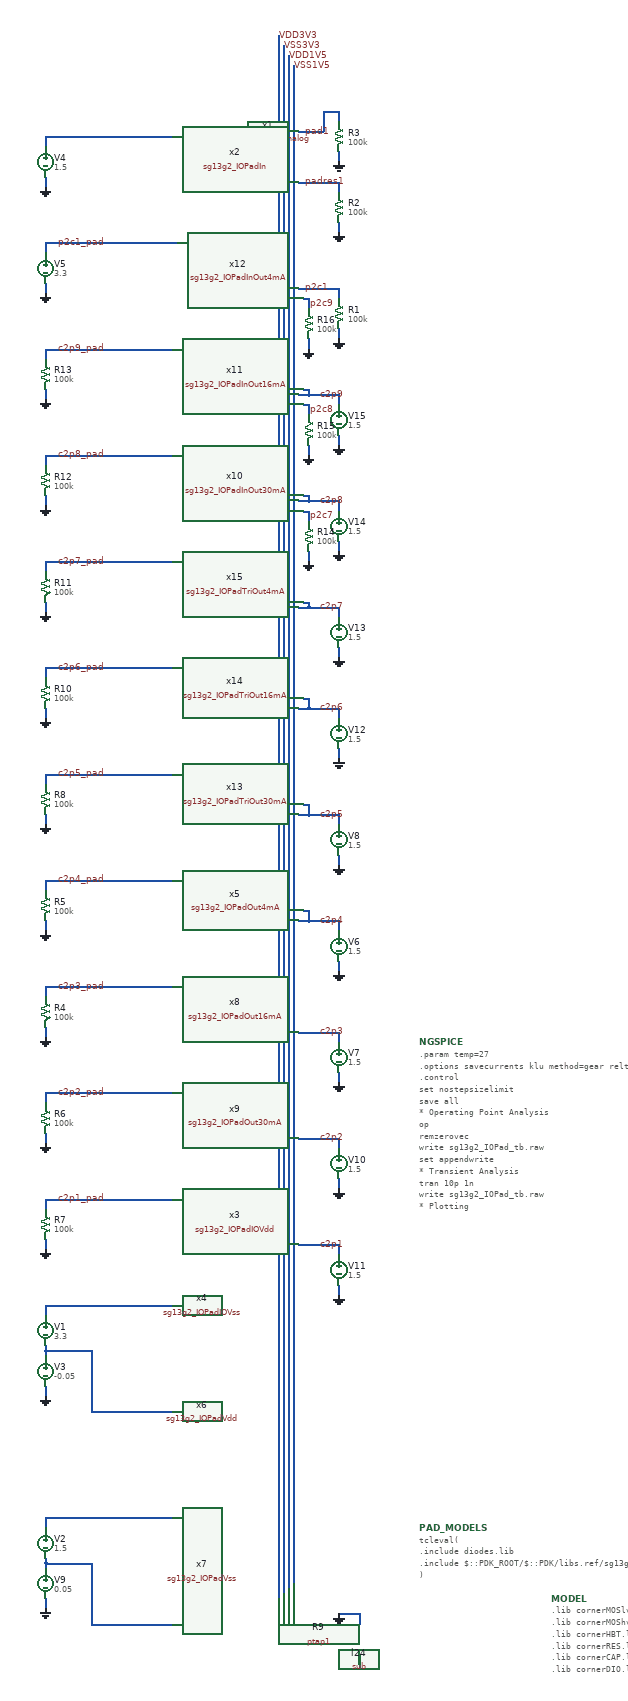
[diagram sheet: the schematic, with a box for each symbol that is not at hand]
v {xschem version=3.4.8RC file_version=1.3}
G {}
K {}
V {}
S {}
F {}
E {}
N 100 -450 100 -430 {lab=VDD1V5}
N 100 -870 100 -850 {lab=VDD3V3}
N 100 -710 100 -690 {lab=GND}
N 100 -3100 100 -3080 {lab=GND}
N 100 -3180 100 -3160 {lab=pad1}
N 100 -2890 100 -2870 {lab=GND}
N 100 -2970 100 -2950 {lab=p2c1_pad}
N 680 -1330 680 -1310 {lab=GND}
N 680 -1410 680 -1390 {lab=c2p3}
N 600 -1410 680 -1410 {lab=c2p3}
N 100 -290 100 -270 {lab=GND}
N 100 -360 100 -350 {lab=VSS1V5}
N 100 -780 100 -770 {lab=VSS3V3}
N 190 -360 190 -240 {lab=VSS1V5}
N 100 -360 190 -360 {lab=VSS1V5}
N 100 -370 100 -360 {lab=VSS1V5}
N 680 -1120 680 -1100 {lab=GND}
N 680 -1200 680 -1180 {lab=c2p2}
N 600 -1200 680 -1200 {lab=c2p2}
N 680 -910 680 -890 {lab=GND}
N 680 -990 680 -970 {lab=c2p1}
N 600 -990 680 -990 {lab=c2p1}
N 720 -180 720 -160 {lab=sub!}
N 720 -260 720 -240 {lab=GND}
N 680 -260 720 -260 {lab=GND}
N 190 -240 350 -240 {lab=VSS1V5}
N 100 -450 350 -450 {lab=VDD1V5}
N 100 -870 350 -870 {lab=VDD3V3}
N 100 -780 190 -780 {lab=VSS3V3}
N 100 -790 100 -780 {lab=VSS3V3}
N 190 -780 190 -660 {lab=VSS3V3}
N 190 -660 350 -660 {lab=VSS3V3}
N 100 -1000 100 -980 {lab=GND}
N 100 -1080 100 -1060 {lab=c2p1_pad}
N 100 -1080 350 -1080 {lab=c2p1_pad}
N 100 -1290 100 -1270 {lab=c2p2_pad}
N 100 -1290 350 -1290 {lab=c2p2_pad}
N 100 -1210 100 -1190 {lab=GND}
N 100 -1500 100 -1480 {lab=c2p3_pad}
N 100 -1500 350 -1500 {lab=c2p3_pad}
N 100 -1420 100 -1400 {lab=GND}
N 680 -2880 680 -2860 {lab=p2c1}
N 600 -2880 680 -2880 {lab=p2c1}
N 680 -2800 680 -2780 {lab=GND}
N 680 -3090 680 -3070 {lab=padres1}
N 680 -3010 680 -2990 {lab=GND}
N 600 -3090 680 -3090 {lab=padres1}
N 680 -3230 680 -3210 {lab=pad1}
N 680 -3150 680 -3130 {lab=GND}
N 600 -3190 650 -3190 {lab=pad1}
N 650 -3230 650 -3190 {lab=pad1}
N 650 -3230 680 -3230 {lab=pad1}
N 100 -2970 360 -2970 {lab=p2c1_pad}
N 100 -3180 350 -3180 {lab=pad1}
N 590 -3320 590 -320 {lab=VSS1V5}
N 580 -3340 580 -310 {lab=VDD1V5}
N 570 -3360 570 -300 {lab=VSS3V3}
N 560 -3380 560 -290 {lab=VDD3V3}
N 680 -1550 680 -1530 {lab=GND}
N 680 -1630 680 -1610 {lab=c2p4}
N 620 -1630 680 -1630 {lab=c2p4}
N 680 -1760 680 -1740 {lab=GND}
N 680 -1840 680 -1820 {lab=c2p5}
N 620 -1840 680 -1840 {lab=c2p5}
N 680 -1970 680 -1950 {lab=GND}
N 680 -2050 680 -2030 {lab=c2p6}
N 620 -2050 680 -2050 {lab=c2p6}
N 680 -2170 680 -2150 {lab=GND}
N 680 -2250 680 -2230 {lab=c2p7}
N 620 -2250 680 -2250 {lab=c2p7}
N 680 -2380 680 -2360 {lab=GND}
N 680 -2460 680 -2440 {lab=c2p8}
N 620 -2460 680 -2460 {lab=c2p8}
N 680 -2590 680 -2570 {lab=GND}
N 680 -2670 680 -2650 {lab=c2p9}
N 620 -2670 680 -2670 {lab=c2p9}
N 100 -1710 100 -1690 {lab=c2p4_pad}
N 100 -1710 350 -1710 {lab=c2p4_pad}
N 100 -1630 100 -1610 {lab=GND}
N 100 -1920 100 -1900 {lab=c2p5_pad}
N 100 -1920 350 -1920 {lab=c2p5_pad}
N 100 -1840 100 -1820 {lab=GND}
N 100 -2130 100 -2110 {lab=c2p6_pad}
N 100 -2130 350 -2130 {lab=c2p6_pad}
N 100 -2050 100 -2030 {lab=GND}
N 100 -2340 100 -2320 {lab=c2p7_pad}
N 100 -2340 350 -2340 {lab=c2p7_pad}
N 100 -2260 100 -2240 {lab=GND}
N 100 -2550 100 -2530 {lab=c2p8_pad}
N 100 -2550 350 -2550 {lab=c2p8_pad}
N 100 -2470 100 -2450 {lab=GND}
N 100 -2760 100 -2740 {lab=c2p9_pad}
N 100 -2760 350 -2760 {lab=c2p9_pad}
N 100 -2680 100 -2660 {lab=GND}
N 610 -2680 620 -2680 {lab=c2p9}
N 620 -2680 620 -2670 {lab=c2p9}
N 600 -2670 620 -2670 {lab=c2p9}
N 610 -2470 620 -2470 {lab=c2p8}
N 620 -2470 620 -2460 {lab=c2p8}
N 600 -2460 620 -2460 {lab=c2p8}
N 610 -2260 620 -2260 {lab=c2p7}
N 620 -2260 620 -2250 {lab=c2p7}
N 600 -2250 620 -2250 {lab=c2p7}
N 610 -2070 620 -2070 {lab=c2p6}
N 620 -2070 620 -2050 {lab=c2p6}
N 600 -2050 620 -2050 {lab=c2p6}
N 610 -1860 620 -1860 {lab=c2p5}
N 620 -1860 620 -1840 {lab=c2p5}
N 600 -1840 620 -1840 {lab=c2p5}
N 610 -1650 620 -1650 {lab=c2p4}
N 620 -1650 620 -1630 {lab=c2p4}
N 600 -1630 620 -1630 {lab=c2p4}
N 620 -2360 620 -2340 {lab=GND}
N 620 -2570 620 -2550 {lab=GND}
N 620 -2780 620 -2760 {lab=GND}
N 610 -2860 620 -2860 {lab=p2c9}
N 610 -2650 620 -2650 {lab=p2c8}
N 620 -2650 620 -2630 {lab=p2c8}
N 610 -2440 620 -2440 {lab=p2c7}
N 620 -2440 620 -2420 {lab=p2c7}
N 620 -2860 620 -2840 {lab=p2c9}
C {vsource.sym} 100 -820 0 0 {name=V1 value=3.3 savecurrent=false}
C {vsource.sym} 100 -400 0 0 {name=V2 value=1.5 savecurrent=false}
C {gnd.sym} 100 -690 0 0 {name=l1 lab=GND}
C {gnd.sym} 100 -270 0 0 {name=l2 lab=GND}
C {lab_wire.sym} 580 -3340 0 1 {name=p2 sig_type=std_logic lab=VDD1V5}
C {vsource.sym} 100 -740 0 0 {name=V3 value=-0.05 savecurrent=false}
C {gnd.sym} 100 -3080 0 0 {name=l3 lab=GND}
C {vsource.sym} 100 -3130 0 0 {name=V4 value=1.5 savecurrent=false}
C {lab_wire.sym} 610 -3090 0 1 {name=p5 sig_type=std_logic lab=padres1}
C {lab_wire.sym} 610 -3190 0 1 {name=p6 sig_type=std_logic lab=pad1}
C {gnd.sym} 680 -2780 0 0 {name=l6 lab=GND}
C {gnd.sym} 100 -2870 0 0 {name=l7 lab=GND}
C {vsource.sym} 100 -2920 0 0 {name=V5 value=3.3 savecurrent=false}
C {res.sym} 680 -2830 0 0 {name=R1
value=100k
footprint=1206
device=resistor
m=1}
C {gnd.sym} 100 -1400 0 0 {name=l9 lab=GND}
C {res.sym} 100 -1450 0 0 {name=R4
value=100k
footprint=1206
device=resistor
m=1}
C {gnd.sym} 680 -1310 0 0 {name=l10 lab=GND}
C {vsource.sym} 680 -1360 0 0 {name=V7 value=1.5 savecurrent=false}
C {lab_wire.sym} 640 -990 0 1 {name=p12 sig_type=std_logic lab=c2p1}
C {lab_wire.sym} 560 -3380 0 1 {name=p14 sig_type=std_logic lab=VDD3V3}
C {lab_wire.sym} 570 -3360 0 1 {name=p15 sig_type=std_logic lab=VSS3V3}
C {vsource.sym} 100 -320 0 0 {name=V9 value=0.05 savecurrent=false}
C {lab_wire.sym} 590 -3320 0 1 {name=p16 sig_type=std_logic lab=VSS1V5}
C {lab_wire.sym} 220 -2970 0 0 {name=p17 sig_type=std_logic lab=p2c1_pad}
C {lab_wire.sym} 220 -1080 0 0 {name=p20 sig_type=std_logic lab=c2p1_pad}
C {lab_wire.sym} 610 -2880 0 1 {name=p4 sig_type=std_logic lab=p2c1}
C {gnd.sym} 100 -1190 0 0 {name=l13 lab=GND}
C {res.sym} 100 -1240 0 0 {name=R6
value=100k
footprint=1206
device=resistor
m=1}
C {gnd.sym} 680 -1100 0 0 {name=l14 lab=GND}
C {vsource.sym} 680 -1150 0 0 {name=V10 value=1.5 savecurrent=false}
C {lab_wire.sym} 640 -1200 0 1 {name=p1 sig_type=std_logic lab=c2p2}
C {lab_wire.sym} 220 -1290 0 0 {name=p3 sig_type=std_logic lab=c2p2_pad}
C {gnd.sym} 100 -980 0 0 {name=l15 lab=GND}
C {res.sym} 100 -1030 0 0 {name=R7
value=100k
footprint=1206
device=resistor
m=1}
C {gnd.sym} 680 -890 0 0 {name=l16 lab=GND}
C {vsource.sym} 680 -940 0 0 {name=V11 value=1.5 savecurrent=false}
C {lab_wire.sym} 640 -1410 0 1 {name=p7 sig_type=std_logic lab=c2p3}
C {lab_wire.sym} 220 -1500 0 0 {name=p8 sig_type=std_logic lab=c2p3_pad}
C {title.sym} 160 -30 0 0 {name=l17 author="Simon Dorrer & Patrick Fath"}
C {sg13g2_pr/sub.sym} 720 -160 0 0 {name=l24 lab=sub!}
C {sg13g2_pr/ptap1.sym} 720 -210 0 0 {name=R9
model=ptap1
spiceprefix=X
w=0.78e-6
l=0.78e-6
}
C {gnd.sym} 680 -260 0 0 {name=l8 lab=GND}
C {sg13g2_io/sg13g2_IOPadAnalog.sym} 250 -3290 1 0 {name=x1}
C {sg13g2_io/sg13g2_IOPadIn.sym} 250 -3080 1 0 {name=x2}
C {sg13g2_io/sg13g2_IOPadIOVdd.sym} 250 -980 1 0 {name=x3}
C {sg13g2_io/sg13g2_IOPadIOVss.sym} 250 -770 1 0 {name=x4}
C {sg13g2_io/sg13g2_IOPadOut4mA.sym} 250 -1610 1 0 {name=x5}
C {sg13g2_io/sg13g2_IOPadVdd.sym} 250 -560 1 0 {name=x6}
C {sg13g2_io/sg13g2_IOPadVss.sym} 250 -350 1 0 {name=x7}
C {sg13g2_io/sg13g2_IOPadOut16mA.sym} 250 -1400 1 0 {name=x8}
C {sg13g2_io/sg13g2_IOPadOut30mA.sym} 250 -1190 1 0 {name=x9}
C {gnd.sym} 680 -2990 0 0 {name=l4 lab=GND}
C {res.sym} 680 -3040 0 0 {name=R2
value=100k
footprint=1206
device=resistor
m=1}
C {gnd.sym} 680 -3130 0 0 {name=l5 lab=GND}
C {res.sym} 680 -3180 0 0 {name=R3
value=100k
footprint=1206
device=resistor
m=1}
C {sg13g2_io/sg13g2_IOPadInOut30mA.sym} 250 -2450 1 0 {name=x10}
C {sg13g2_io/sg13g2_IOPadInOut16mA.sym} 250 -2660 1 0 {name=x11}
C {sg13g2_io/sg13g2_IOPadInOut4mA.sym} 250 -2870 1 0 {name=x12}
C {sg13g2_io/sg13g2_IOPadTriOut30mA.sym} 250 -1820 1 0 {name=x13}
C {sg13g2_io/sg13g2_IOPadTriOut16mA.sym} 250 -2030 1 0 {name=x14}
C {sg13g2_io/sg13g2_IOPadTriOut4mA.sym} 250 -2240 1 0 {name=x15}
C {gnd.sym} 680 -1530 0 0 {name=l11 lab=GND}
C {vsource.sym} 680 -1580 0 0 {name=V6 value=1.5 savecurrent=false}
C {lab_wire.sym} 640 -1630 0 1 {name=p9 sig_type=std_logic lab=c2p4}
C {gnd.sym} 680 -1740 0 0 {name=l12 lab=GND}
C {vsource.sym} 680 -1790 0 0 {name=V8 value=1.5 savecurrent=false}
C {lab_wire.sym} 640 -1840 0 1 {name=p10 sig_type=std_logic lab=c2p5}
C {gnd.sym} 680 -1950 0 0 {name=l18 lab=GND}
C {vsource.sym} 680 -2000 0 0 {name=V12 value=1.5 savecurrent=false}
C {lab_wire.sym} 640 -2050 0 1 {name=p11 sig_type=std_logic lab=c2p6}
C {gnd.sym} 680 -2150 0 0 {name=l19 lab=GND}
C {vsource.sym} 680 -2200 0 0 {name=V13 value=1.5 savecurrent=false}
C {lab_wire.sym} 640 -2250 0 1 {name=p13 sig_type=std_logic lab=c2p7}
C {gnd.sym} 680 -2360 0 0 {name=l20 lab=GND}
C {vsource.sym} 680 -2410 0 0 {name=V14 value=1.5 savecurrent=false}
C {lab_wire.sym} 640 -2460 0 1 {name=p18 sig_type=std_logic lab=c2p8}
C {gnd.sym} 680 -2570 0 0 {name=l21 lab=GND}
C {vsource.sym} 680 -2620 0 0 {name=V15 value=1.5 savecurrent=false}
C {lab_wire.sym} 640 -2670 0 1 {name=p19 sig_type=std_logic lab=c2p9}
C {gnd.sym} 100 -1610 0 0 {name=l22 lab=GND}
C {res.sym} 100 -1660 0 0 {name=R5
value=100k
footprint=1206
device=resistor
m=1}
C {lab_wire.sym} 220 -1710 0 0 {name=p21 sig_type=std_logic lab=c2p4_pad}
C {gnd.sym} 100 -1820 0 0 {name=l23 lab=GND}
C {res.sym} 100 -1870 0 0 {name=R8
value=100k
footprint=1206
device=resistor
m=1}
C {lab_wire.sym} 220 -1920 0 0 {name=p22 sig_type=std_logic lab=c2p5_pad}
C {gnd.sym} 100 -2030 0 0 {name=l25 lab=GND}
C {res.sym} 100 -2080 0 0 {name=R10
value=100k
footprint=1206
device=resistor
m=1}
C {lab_wire.sym} 220 -2130 0 0 {name=p23 sig_type=std_logic lab=c2p6_pad}
C {gnd.sym} 100 -2240 0 0 {name=l26 lab=GND}
C {res.sym} 100 -2290 0 0 {name=R11
value=100k
footprint=1206
device=resistor
m=1}
C {lab_wire.sym} 220 -2340 0 0 {name=p24 sig_type=std_logic lab=c2p7_pad}
C {gnd.sym} 100 -2450 0 0 {name=l27 lab=GND}
C {res.sym} 100 -2500 0 0 {name=R12
value=100k
footprint=1206
device=resistor
m=1}
C {lab_wire.sym} 220 -2550 0 0 {name=p25 sig_type=std_logic lab=c2p8_pad}
C {gnd.sym} 100 -2660 0 0 {name=l28 lab=GND}
C {res.sym} 100 -2710 0 0 {name=R13
value=100k
footprint=1206
device=resistor
m=1}
C {lab_wire.sym} 220 -2760 0 0 {name=p26 sig_type=std_logic lab=c2p9_pad}
C {gnd.sym} 620 -2340 0 0 {name=l29 lab=GND}
C {res.sym} 620 -2390 0 0 {name=R14
value=100k
footprint=1206
device=resistor
m=1}
C {gnd.sym} 620 -2550 0 0 {name=l30 lab=GND}
C {res.sym} 620 -2600 0 0 {name=R15
value=100k
footprint=1206
device=resistor
m=1}
C {gnd.sym} 620 -2760 0 0 {name=l31 lab=GND}
C {res.sym} 620 -2810 0 0 {name=R16
value=100k
footprint=1206
device=resistor
m=1}
C {lab_wire.sym} 620 -2850 0 1 {name=p27 sig_type=std_logic lab=p2c9}
C {lab_wire.sym} 620 -2640 0 1 {name=p28 sig_type=std_logic lab=p2c8}
C {lab_wire.sym} 620 -2430 0 1 {name=p29 sig_type=std_logic lab=p2c7}
C {devices/code_shown.sym} 840 -1390 0 0 {name=NGSPICE
only_toplevel=true 
value="
.param temp=27
.options savecurrents klu method=gear reltol=1e-3 abstol=1e-15 gmin=1e-15 chgtol=1e-11
.control

set nostepsizelimit

save all

* Operating Point Analysis
op
remzerovec
write sg13g2_IOPad_tb.raw
set appendwrite

* Transient Analysis
tran 10p 1n
write sg13g2_IOPad_tb.raw

* Plotting
plot VDD3V3 VSS3V3 VDD1V5 VSS1V5

* Analog
plot pad1 padres1

* In
plot p2c1 p2c1_pad

* InOut
plot c2p9 c2p9_pad p2c9
plot c2p8 c2p8_pad p2c8
plot c2p7 c2p7_pad p2c7

* TriOut
plot c2p6 c2p6_pad
plot c2p5 c2p5_pad
plot c2p4 c2p4_pad

* Out
plot c2p3 c2p3_pad
plot c2p2 c2p2_pad
plot c2p1 c2p1_pad

*quit
.endc
"}
C {devices/launcher.sym} 900 -260 0 0 {name=h1
descr="Simulate" 
tclcommand="xschem save; xschem netlist; xschem simulate"
}
C {devices/launcher.sym} 900 -200 0 0 {name=h5
descr="Annotate OP" 
tclcommand="set show_hidden_texts 1; xschem annotate_op"
}
C {devices/code_shown.sym} 1100 -290 0 0 {name=MODEL only_toplevel=true
format="tcleval( @value )"
value="
.lib cornerMOSlv.lib mos_tt
.lib cornerMOShv.lib mos_tt
.lib cornerHBT.lib hbt_typ
.lib cornerRES.lib res_typ
.lib cornerCAP.lib cap_typ
.lib cornerDIO.lib dio_tt
"}
C {code_shown.sym} 840 -430 0 0 {name=PAD_MODELS
only_toplevel=true
value="tcleval(
.include diodes.lib
.include $::PDK_ROOT/$::PDK/libs.ref/sg13g2_io/spice/sg13g2_io.spi
)"
spice_ignore=false
      }
